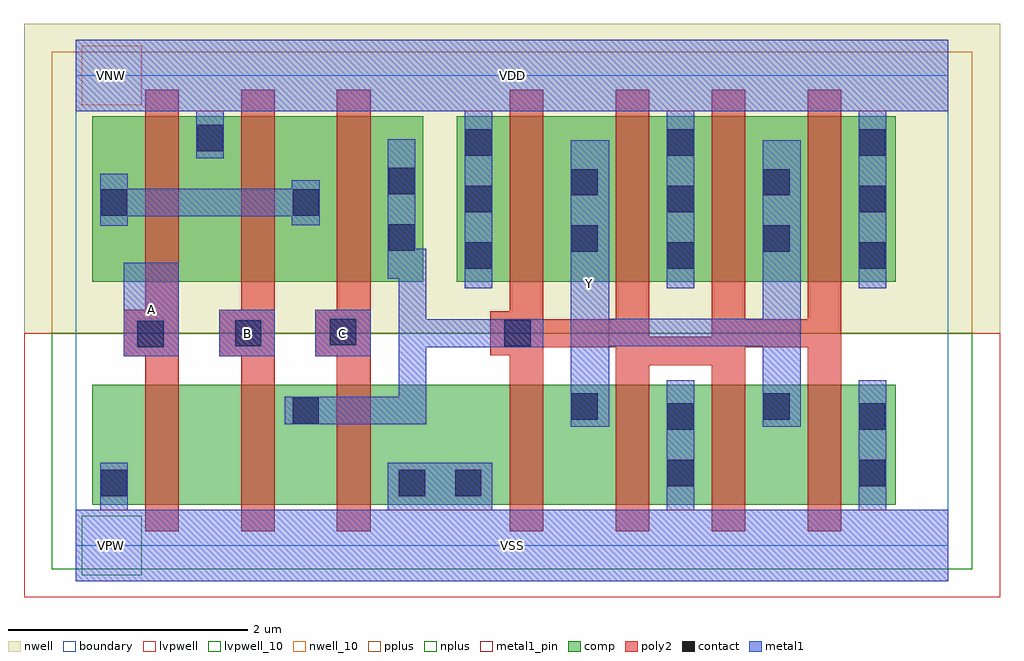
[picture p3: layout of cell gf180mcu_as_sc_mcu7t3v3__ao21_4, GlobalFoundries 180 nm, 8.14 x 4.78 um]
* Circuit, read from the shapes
.subckt gf180mcu_as_sc_mcu7t3v3__ao21_4 A B C VDD VNW VSS Y
XM1 n1 A VSS VSUBS nfet_03v3 w=1u l=0.28u
XM2 n2 B n1 VSUBS nfet_03v3 w=1u l=0.28u
XM3 VSS C n2 VSUBS nfet_03v3 w=1u l=0.28u
XM4 Y n2 VSS VSUBS nfet_03v3 w=1u l=0.28u m=4
XM5 VDD A n3 VNW pfet_03v3 w=1.38u l=0.28u
XM6 n3 B VDD VNW pfet_03v3 w=1.38u l=0.28u
XM7 n2 C n3 VNW pfet_03v3 w=1.38u l=0.28u
XM8 Y n2 VDD VNW pfet_03v3 w=1.38u l=0.28u m=4
.ends

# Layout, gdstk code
import gdstk
lib = gdstk.Library(unit=1e-6, precision=1e-09)
def R(c, l, rs):  # rectangles x0, y0, x1, y1
    for r in rs: c.add(gdstk.rectangle(r[:2], r[2:], *l))
def A(c, l, x, y, w, h, nx, ny, dx, dy):  # array of equal rectangles
    R(c, l, [(x+i*dx, y+j*dy, x+i*dx+w, y+j*dy+h) for i in range(nx) for j in range(ny)])
boundary = (0, 0)
nwell = (21, 0)
nwell_10 = (21, 10)
comp = (22, 0)
poly2 = (30, 0)
pplus = (31, 0)
nplus = (32, 0)
contact = (33, 0)
metal1 = (34, 0)
metal1_pin = (34, 10)
lvpwell = (204, 0)
lvpwell_10 = (204, 10)

gf180mcu_as_sc_mcu7t3v3_ = lib.new_cell('gf180mcu_as_sc_mcu7t3v3__ao21_4')
R(gf180mcu_as_sc_mcu7t3v3_, boundary, [(0,0,7.28,3.92)])
R(gf180mcu_as_sc_mcu7t3v3_, nwell, [(-0.43,1.77,7.71,4.35)])
R(gf180mcu_as_sc_mcu7t3v3_, nwell_10, [(0.05,3.67,0.55,4.17)])
R(gf180mcu_as_sc_mcu7t3v3_, comp, [(0.14,0.34,6.84,1.34), (0.14,2.2,2.9,3.58), (3.18,2.2,6.84,3.58)])
A(gf180mcu_as_sc_mcu7t3v3_, poly2, 0.58, 0.12, 0.28, 1.46, 3, 1, 0.8, 0)
A(gf180mcu_as_sc_mcu7t3v3_, poly2, 0.4, 1.58, 0.46, 0.385, 3, 1, 0.8, 0)
A(gf180mcu_as_sc_mcu7t3v3_, poly2, 4.505, 1.885, 0.28, 1.915, 3, 1, 0.8, 0)
A(gf180mcu_as_sc_mcu7t3v3_, poly2, 0.58, 1.965, 0.28, 1.835, 3, 1, 0.8, 0)
R(gf180mcu_as_sc_mcu7t3v3_, poly2, [(3.62,0.12,3.9,1.585), (4.505,0.12,4.785,1.505), (5.305,0.12,5.585,1.505), (6.105,0.12,6.385,1.655), (4.505,1.505,5.585,1.655), (3.46,1.585,3.9,1.655), (3.46,1.655,6.385,1.74), (3.46,1.74,4.785,1.885), (5.305,1.74,6.385,1.885), (3.46,1.885,3.9,1.955), (3.62,1.955,3.9,3.8)])
R(gf180mcu_as_sc_mcu7t3v3_, pplus, [(-0.2,1.77,7.48,4.12)])
R(gf180mcu_as_sc_mcu7t3v3_, nplus, [(-0.2,-0.2,7.48,1.77)])
A(gf180mcu_as_sc_mcu7t3v3_, contact, 3.25, 2.31, 0.22, 0.22, 1, 3, 0, 0.47)
A(gf180mcu_as_sc_mcu7t3v3_, contact, 4.935, 2.31, 0.22, 0.22, 1, 3, 0, 0.47)
A(gf180mcu_as_sc_mcu7t3v3_, contact, 6.535, 2.31, 0.22, 0.22, 1, 3, 0, 0.47)
R(gf180mcu_as_sc_mcu7t3v3_, contact, [(0.21,0.41,0.43,0.63), (2.695,0.41,2.915,0.63), (3.165,0.41,3.385,0.63), (4.935,0.495,5.155,0.715), (6.535,0.495,6.755,0.715), (4.935,0.965,5.155,1.185), (6.535,0.965,6.755,1.185), (1.81,1.015,2.03,1.235), (4.135,1.05,4.355,1.27), (5.735,1.05,5.955,1.27), (0.515,1.655,0.735,1.875), (1.33,1.66,1.55,1.88), (3.575,1.66,3.795,1.88), (2.12,1.67,2.34,1.89), (4.135,2.45,4.355,2.67), (5.735,2.45,5.955,2.67), (2.61,2.46,2.83,2.68), (0.21,2.75,0.43,2.97), (1.81,2.75,2.03,2.97), (4.135,2.92,4.355,3.14), (5.735,2.92,5.955,3.14), (2.61,2.93,2.83,3.15), (1.01,3.29,1.23,3.51)])
R(gf180mcu_as_sc_mcu7t3v3_, metal1, [(0,-0.3,7.28,0.3), (0.205,0.3,0.435,0.69), (2.605,0.3,3.475,0.69), (4.93,0.3,5.16,1.38), (6.53,0.3,6.76,1.38), (4.13,0.99,4.45,1.66), (5.73,0.99,6.05,1.66), (1.745,1.01,2.925,1.24), (2.695,1.24,2.925,1.655), (0.4,1.58,0.86,2.36), (1.2,1.58,1.66,1.965), (2,1.58,2.46,1.965), (2.695,1.655,3.9,1.885), (4.13,1.66,6.05,1.89), (2.695,1.885,2.925,2.225), (4.13,1.89,4.45,3.38), (5.73,1.89,6.05,3.38), (3.245,2.145,3.475,3.62), (4.93,2.145,5.16,3.62), (6.53,2.145,6.76,3.62), (2.605,2.225,2.925,2.475), (2.605,2.475,2.835,3.39), (0.205,2.665,0.435,2.745), (1.805,2.67,2.035,2.745), (0.205,2.745,2.035,2.975), (0.205,2.975,0.435,3.1), (1.805,2.975,2.035,3.045), (1.005,3.23,1.235,3.62), (0,3.62,7.28,4.22)])
R(gf180mcu_as_sc_mcu7t3v3_, metal1_pin, [(0,-0.3,7.28,0.3), (4.13,0.99,4.45,3.38), (0.4,1.58,0.86,2.36), (1.2,1.58,1.66,1.965), (2,1.58,2.46,1.965), (0,3.62,7.28,4.22)])
R(gf180mcu_as_sc_mcu7t3v3_, lvpwell, [(-0.43,-0.43,7.71,1.77)])
R(gf180mcu_as_sc_mcu7t3v3_, lvpwell_10, [(0.05,-0.25,0.55,0.25)])
gf180mcu_as_sc_mcu7t3v3_.add(gdstk.Label('VDD', (3.64,3.92), layer=34, texttype=10))
gf180mcu_as_sc_mcu7t3v3_.add(gdstk.Label('VSS', (3.64,0), layer=34, texttype=10))
gf180mcu_as_sc_mcu7t3v3_.add(gdstk.Label('Y', (4.29,2.185), layer=34, texttype=10))
gf180mcu_as_sc_mcu7t3v3_.add(gdstk.Label('A', (0.63,1.97), layer=34, texttype=10))
gf180mcu_as_sc_mcu7t3v3_.add(gdstk.Label('B', (1.43,1.772), layer=34, texttype=10))
gf180mcu_as_sc_mcu7t3v3_.add(gdstk.Label('C', (2.23,1.772), layer=34, texttype=10))
gf180mcu_as_sc_mcu7t3v3_.add(gdstk.Label('VNW', (0.3,3.92), layer=21, texttype=10))
gf180mcu_as_sc_mcu7t3v3_.add(gdstk.Label('VPW', (0.3,0), layer=204, texttype=10))

lib.write_gds('gf180mcu_as_sc_mcu7t3v3__ao21_4.gds')
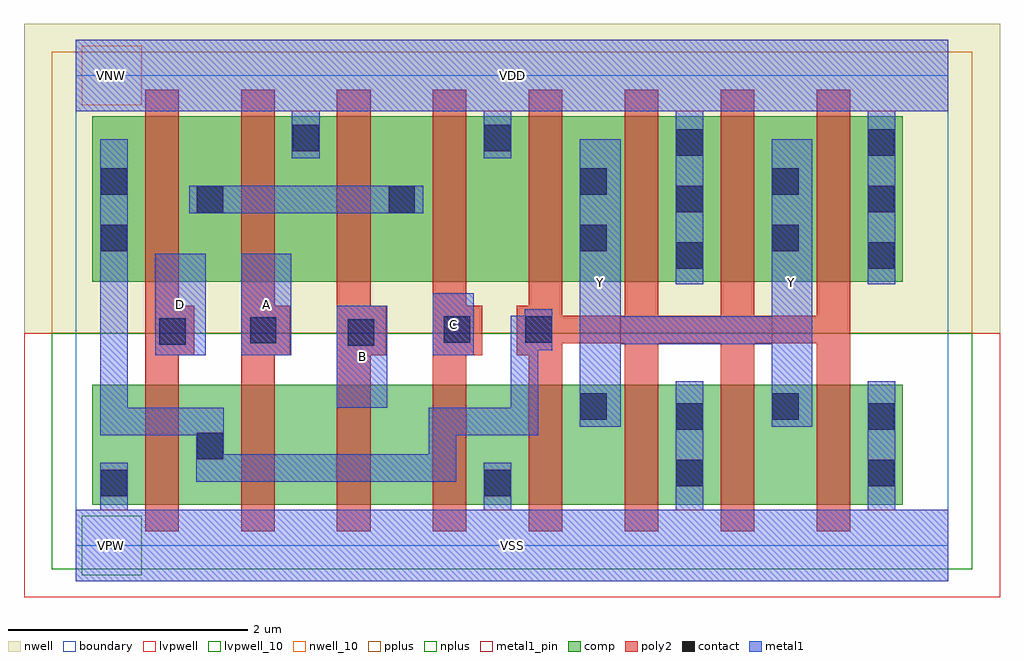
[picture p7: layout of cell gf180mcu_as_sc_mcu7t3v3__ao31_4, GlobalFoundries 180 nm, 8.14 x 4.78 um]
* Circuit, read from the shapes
.subckt gf180mcu_as_sc_mcu7t3v3__ao31_4 A B C D VDD VNW VSS Y
XM1 n1 D VSS VSUBS nfet_03v3 w=1u l=0.28u
XM2 n2 A n1 VSUBS nfet_03v3 w=1u l=0.28u
XM3 n3 B n2 VSUBS nfet_03v3 w=1u l=0.28u
XM4 VSS C n3 VSUBS nfet_03v3 w=1u l=0.28u
XM5 Y n1 VSS VSUBS nfet_03v3 w=1u l=0.28u m=4
XM6 n4 D n1 VNW pfet_03v3 w=1.38u l=0.28u
XM7 VDD A n4 VNW pfet_03v3 w=1.38u l=0.28u
XM8 n4 B VDD VNW pfet_03v3 w=1.38u l=0.28u
XM9 VDD C n4 VNW pfet_03v3 w=1.38u l=0.28u
XM10 Y n1 VDD VNW pfet_03v3 w=1.38u l=0.28u m=4
.ends

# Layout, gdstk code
import gdstk
lib = gdstk.Library(unit=1e-6, precision=1e-09)
def R(c, l, rs):  # rectangles x0, y0, x1, y1
    for r in rs: c.add(gdstk.rectangle(r[:2], r[2:], *l))
def A(c, l, x, y, w, h, nx, ny, dx, dy):  # array of equal rectangles
    R(c, l, [(x+i*dx, y+j*dy, x+i*dx+w, y+j*dy+h) for i in range(nx) for j in range(ny)])
boundary = (0, 0)
nwell = (21, 0)
nwell_10 = (21, 10)
comp = (22, 0)
poly2 = (30, 0)
pplus = (31, 0)
nplus = (32, 0)
contact = (33, 0)
metal1 = (34, 0)
metal1_pin = (34, 10)
lvpwell = (204, 0)
lvpwell_10 = (204, 10)

gf180mcu_as_sc_mcu7t3v3_ = lib.new_cell('gf180mcu_as_sc_mcu7t3v3__ao31_4')
R(gf180mcu_as_sc_mcu7t3v3_, boundary, [(0,0,7.28,3.92)])
R(gf180mcu_as_sc_mcu7t3v3_, nwell, [(-0.43,1.77,7.71,4.35)])
R(gf180mcu_as_sc_mcu7t3v3_, nwell_10, [(0.05,3.67,0.55,4.17)])
R(gf180mcu_as_sc_mcu7t3v3_, comp, [(0.14,0.34,6.9,1.34), (0.14,2.2,6.9,3.58)])
A(gf180mcu_as_sc_mcu7t3v3_, poly2, 0.58, 0.12, 0.28, 1.465, 5, 1, 0.8, 0)
A(gf180mcu_as_sc_mcu7t3v3_, poly2, 4.58, 0.12, 0.28, 1.565, 3, 1, 0.8, 0)
A(gf180mcu_as_sc_mcu7t3v3_, poly2, 0.58, 1.585, 0.41, 0.415, 4, 1, 0.8, 0)
A(gf180mcu_as_sc_mcu7t3v3_, poly2, 4.58, 1.915, 0.28, 1.885, 3, 1, 0.8, 0)
A(gf180mcu_as_sc_mcu7t3v3_, poly2, 0.58, 2, 0.28, 1.8, 5, 1, 0.8, 0)
R(gf180mcu_as_sc_mcu7t3v3_, poly2, [(3.68,1.585,4.06,1.685), (3.68,1.685,6.46,1.915), (3.68,1.915,4.06,2)])
R(gf180mcu_as_sc_mcu7t3v3_, pplus, [(-0.2,1.77,7.48,4.12)])
R(gf180mcu_as_sc_mcu7t3v3_, nplus, [(-0.2,-0.2,7.48,1.77)])
A(gf180mcu_as_sc_mcu7t3v3_, contact, 5.01, 2.31, 0.22, 0.22, 1, 3, 0, 0.47)
A(gf180mcu_as_sc_mcu7t3v3_, contact, 6.61, 2.31, 0.22, 0.22, 1, 3, 0, 0.47)
R(gf180mcu_as_sc_mcu7t3v3_, contact, [(0.21,0.41,0.43,0.63), (3.41,0.41,3.63,0.63), (5.01,0.495,5.23,0.715), (6.61,0.495,6.83,0.715), (1.01,0.72,1.23,0.94), (5.01,0.965,5.23,1.185), (6.61,0.965,6.83,1.185), (4.21,1.05,4.43,1.27), (5.81,1.05,6.03,1.27), (2.27,1.665,2.49,1.885), (0.7,1.675,0.92,1.895), (1.455,1.685,1.675,1.905), (3.07,1.69,3.29,1.91), (3.75,1.69,3.97,1.91), (0.21,2.455,0.43,2.675), (4.21,2.455,4.43,2.675), (5.81,2.455,6.03,2.675), (1.01,2.775,1.23,2.995), (2.61,2.775,2.83,2.995), (0.21,2.925,0.43,3.145), (4.21,2.925,4.43,3.145), (5.81,2.925,6.03,3.145), (1.81,3.29,2.03,3.51), (3.41,3.29,3.63,3.51)])
R(gf180mcu_as_sc_mcu7t3v3_, metal1, [(0,-0.3,7.28,0.3), (0.205,0.3,0.435,0.69), (3.405,0.3,3.635,0.69), (5.005,0.3,5.235,1.37), (6.605,0.3,6.835,1.37), (1.005,0.53,3.175,0.76), (1.005,0.76,1.235,0.92), (2.945,0.76,3.175,0.92), (0.205,0.92,1.235,1.15), (2.945,0.92,3.86,1.15), (4.205,0.99,4.545,1.68), (5.805,0.99,6.145,1.68), (0.205,1.15,0.435,3.39), (2.18,1.15,2.6,2), (3.63,1.15,3.86,1.63), (0.665,1.585,1.085,2.435), (1.38,1.585,1.8,2.435), (2.98,1.585,3.32,2.105), (3.63,1.63,3.975,1.915), (4.205,1.68,6.145,1.91), (4.205,1.91,4.545,3.39), (5.805,1.91,6.145,3.39), (3.745,1.915,3.975,1.97), (5.005,2.18,5.235,3.62), (6.605,2.18,6.835,3.62), (0.95,2.77,2.9,3), (1.805,3.23,2.035,3.62), (3.405,3.23,3.635,3.62), (0,3.62,7.28,4.22)])
R(gf180mcu_as_sc_mcu7t3v3_, metal1_pin, [(0,-0.3,7.28,0.3), (4.205,0.99,4.545,3.39), (5.805,0.99,6.145,3.39), (2.18,1.15,2.6,2), (0.665,1.585,1.085,2.435), (1.38,1.585,1.8,2.435), (2.98,1.585,3.32,2.105), (0,3.62,7.28,4.22)])
R(gf180mcu_as_sc_mcu7t3v3_, lvpwell, [(-0.43,-0.43,7.71,1.77)])
R(gf180mcu_as_sc_mcu7t3v3_, lvpwell_10, [(0.05,-0.25,0.55,0.25)])
gf180mcu_as_sc_mcu7t3v3_.add(gdstk.Label('VDD', (3.64,3.92), layer=34, texttype=10))
gf180mcu_as_sc_mcu7t3v3_.add(gdstk.Label('VSS', (3.64,0), layer=34, texttype=10))
gf180mcu_as_sc_mcu7t3v3_.add(gdstk.Label('D', (0.875,2.01), layer=34, texttype=10))
gf180mcu_as_sc_mcu7t3v3_.add(gdstk.Label('A', (1.59,2.01), layer=34, texttype=10))
gf180mcu_as_sc_mcu7t3v3_.add(gdstk.Label('B', (2.39,1.575), layer=34, texttype=10))
gf180mcu_as_sc_mcu7t3v3_.add(gdstk.Label('C', (3.15,1.845), layer=34, texttype=10))
gf180mcu_as_sc_mcu7t3v3_.add(gdstk.Label('Y', (5.975,2.19), layer=34, texttype=10))
gf180mcu_as_sc_mcu7t3v3_.add(gdstk.Label('Y', (4.375,2.19), layer=34, texttype=10))
gf180mcu_as_sc_mcu7t3v3_.add(gdstk.Label('VNW', (0.3,3.92), layer=21, texttype=10))
gf180mcu_as_sc_mcu7t3v3_.add(gdstk.Label('VPW', (0.3,0), layer=204, texttype=10))

lib.write_gds('gf180mcu_as_sc_mcu7t3v3__ao31_4.gds')
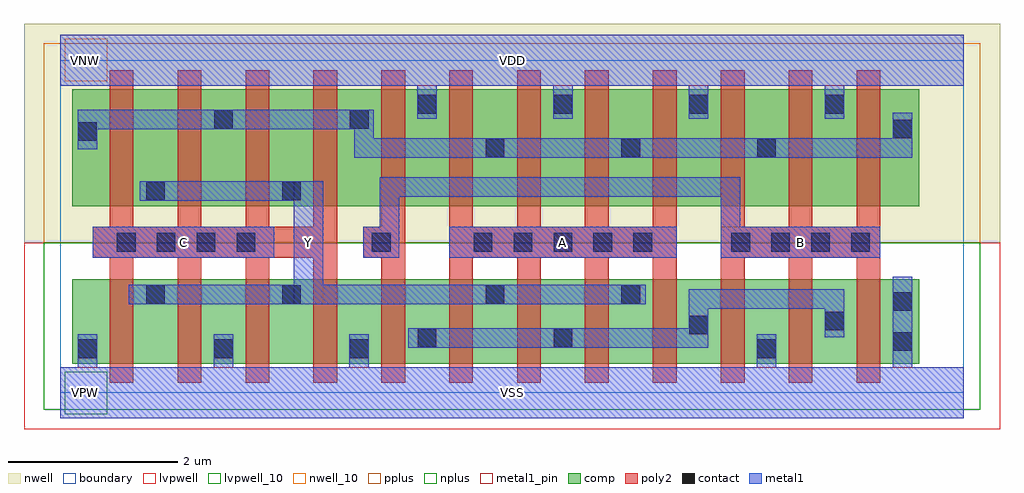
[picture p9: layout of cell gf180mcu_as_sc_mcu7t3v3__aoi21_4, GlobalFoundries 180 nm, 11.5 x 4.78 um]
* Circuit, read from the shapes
.subckt gf180mcu_as_sc_mcu7t3v3__aoi21_4 A B C VDD VNW VSS Y
XM1 Y C VSS VSUBS nfet_03v3 w=1u l=0.28u m=4
XM2 n1 B VSS VSUBS nfet_03v3 w=1u l=0.28u m=4
XM3 Y A n1 VSUBS nfet_03v3 w=1u l=0.28u m=4
XM4 Y C n2 VNW pfet_03v3 w=1.38u l=0.28u m=4
XM5 VDD B n2 VNW pfet_03v3 w=1.38u l=0.28u m=4
XM6 n2 A VDD VNW pfet_03v3 w=1.38u l=0.28u m=4
.ends

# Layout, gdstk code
import gdstk
lib = gdstk.Library(unit=1e-6, precision=1e-09)
def R(c, l, rs):  # rectangles x0, y0, x1, y1
    for r in rs: c.add(gdstk.rectangle(r[:2], r[2:], *l))
def A(c, l, x, y, w, h, nx, ny, dx, dy):  # array of equal rectangles
    R(c, l, [(x+i*dx, y+j*dy, x+i*dx+w, y+j*dy+h) for i in range(nx) for j in range(ny)])
boundary = (0, 0)
nwell = (21, 0)
nwell_10 = (21, 10)
comp = (22, 0)
poly2 = (30, 0)
pplus = (31, 0)
nplus = (32, 0)
contact = (33, 0)
metal1 = (34, 0)
metal1_pin = (34, 10)
lvpwell = (204, 0)
lvpwell_10 = (204, 10)

gf180mcu_as_sc_mcu7t3v3_ = lib.new_cell('gf180mcu_as_sc_mcu7t3v3__aoi21_4')
R(gf180mcu_as_sc_mcu7t3v3_, boundary, [(0,0,10.64,3.92)])
R(gf180mcu_as_sc_mcu7t3v3_, nwell, [(-0.43,1.77,11.07,4.35)])
R(gf180mcu_as_sc_mcu7t3v3_, nwell_10, [(0.05,3.67,0.55,4.17)])
R(gf180mcu_as_sc_mcu7t3v3_, comp, [(0.14,0.34,10.12,1.34), (0.14,2.2,10.12,3.58)])
A(gf180mcu_as_sc_mcu7t3v3_, poly2, 0.58, 0.12, 0.28, 1.47, 12, 1, 0.8, 0)
A(gf180mcu_as_sc_mcu7t3v3_, poly2, 0.58, 1.955, 0.28, 1.845, 12, 1, 0.8, 0)
R(gf180mcu_as_sc_mcu7t3v3_, poly2, [(0.38,1.59,3.26,1.955), (3.565,1.59,4.06,1.955), (4.58,1.59,7.26,1.955), (7.78,1.59,9.66,1.955)])
R(gf180mcu_as_sc_mcu7t3v3_, pplus, [(-0.2,1.77,10.84,4.12)])
R(gf180mcu_as_sc_mcu7t3v3_, nplus, [(-0.2,-0.2,10.84,1.77)])
A(gf180mcu_as_sc_mcu7t3v3_, contact, 0.21, 0.41, 0.22, 0.22, 3, 1, 1.6, 0)
A(gf180mcu_as_sc_mcu7t3v3_, contact, 0.665, 1.665, 0.22, 0.22, 4, 1, 0.47, 0)
A(gf180mcu_as_sc_mcu7t3v3_, contact, 4.87, 1.665, 0.22, 0.22, 5, 1, 0.47, 0)
A(gf180mcu_as_sc_mcu7t3v3_, contact, 7.905, 1.665, 0.22, 0.22, 4, 1, 0.47, 0)
A(gf180mcu_as_sc_mcu7t3v3_, contact, 5.01, 2.775, 0.22, 0.22, 3, 1, 1.6, 0)
A(gf180mcu_as_sc_mcu7t3v3_, contact, 4.21, 3.29, 0.22, 0.22, 4, 1, 1.6, 0)
R(gf180mcu_as_sc_mcu7t3v3_, contact, [(8.21,0.41,8.43,0.63), (9.81,0.495,10.03,0.715), (4.21,0.535,4.43,0.755), (5.81,0.535,6.03,0.755), (7.41,0.69,7.63,0.91), (9.01,0.735,9.23,0.955), (9.81,0.965,10.03,1.185), (1.01,1.05,1.23,1.27), (2.61,1.05,2.83,1.27), (5.01,1.05,5.23,1.27), (6.61,1.05,6.83,1.27), (3.67,1.665,3.89,1.885), (1.01,2.27,1.23,2.49), (2.61,2.27,2.83,2.49), (0.21,2.97,0.43,3.19), (9.81,3,10.03,3.22), (1.81,3.11,2.03,3.33), (3.41,3.11,3.63,3.33)])
A(gf180mcu_as_sc_mcu7t3v3_, metal1, 0.205, 0.3, 0.23, 0.39, 3, 1, 1.6, 0)
A(gf180mcu_as_sc_mcu7t3v3_, metal1, 4.205, 3.23, 0.23, 0.39, 4, 1, 1.6, 0)
R(gf180mcu_as_sc_mcu7t3v3_, metal1, [(0,-0.3,10.64,0.3), (8.205,0.3,8.435,0.69), (9.805,0.3,10.035,1.37), (4.1,0.53,7.635,0.76), (9.005,0.655,9.235,0.99), (7.405,0.76,7.635,0.99), (7.405,0.99,9.235,1.22), (0.805,1.045,6.895,1.275), (2.75,1.275,3.095,2.265), (0.38,1.59,2.52,1.955), (3.565,1.59,3.99,1.955), (4.58,1.59,7.26,1.955), (7.78,1.59,9.66,1.955), (3.76,1.955,3.99,2.31), (7.78,1.955,8.01,2.31), (0.935,2.265,3.095,2.495), (3.76,2.31,8.01,2.54), (3.46,2.77,10.035,3), (0.205,2.87,0.435,3.105), (3.46,3,3.69,3.105), (9.805,3,10.035,3.3), (0.205,3.105,3.69,3.335), (0,3.62,10.64,4.22)])
R(gf180mcu_as_sc_mcu7t3v3_, metal1_pin, [(0,-0.3,10.64,0.3), (2.75,1.045,3.095,2.495), (0.38,1.59,2.52,1.955), (4.58,1.59,7.26,1.955), (7.78,1.59,9.66,1.955), (0,3.62,10.64,4.22)])
R(gf180mcu_as_sc_mcu7t3v3_, lvpwell, [(-0.43,-0.43,11.07,1.77)])
R(gf180mcu_as_sc_mcu7t3v3_, lvpwell_10, [(0.05,-0.25,0.55,0.25)])
gf180mcu_as_sc_mcu7t3v3_.add(gdstk.Label('VDD', (5.32,3.92), layer=34, texttype=10))
gf180mcu_as_sc_mcu7t3v3_.add(gdstk.Label('VSS', (5.32,0), layer=34, texttype=10))
gf180mcu_as_sc_mcu7t3v3_.add(gdstk.Label('Y', (2.922,1.77), layer=34, texttype=10))
gf180mcu_as_sc_mcu7t3v3_.add(gdstk.Label('C', (1.45,1.772), layer=34, texttype=10))
gf180mcu_as_sc_mcu7t3v3_.add(gdstk.Label('B', (8.72,1.772), layer=34, texttype=10))
gf180mcu_as_sc_mcu7t3v3_.add(gdstk.Label('A', (5.92,1.772), layer=34, texttype=10))
gf180mcu_as_sc_mcu7t3v3_.add(gdstk.Label('VNW', (0.3,3.92), layer=21, texttype=10))
gf180mcu_as_sc_mcu7t3v3_.add(gdstk.Label('VPW', (0.3,0), layer=204, texttype=10))

lib.write_gds('gf180mcu_as_sc_mcu7t3v3__aoi21_4.gds')
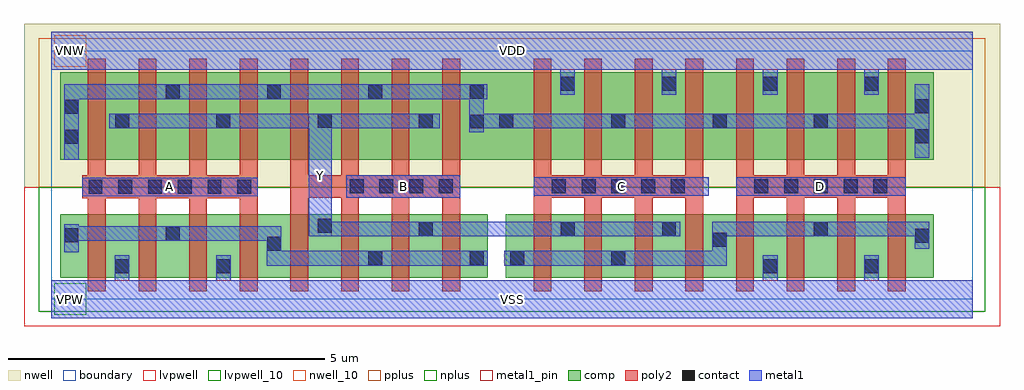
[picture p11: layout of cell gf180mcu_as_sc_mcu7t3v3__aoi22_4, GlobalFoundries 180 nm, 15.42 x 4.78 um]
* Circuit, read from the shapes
.subckt gf180mcu_as_sc_mcu7t3v3__aoi22_4 A B C D VDD VNW VSS Y
XM1 VSS A n1 VSUBS nfet_03v3 w=1u l=0.28u m=4
XM2 Y B n1 VSUBS nfet_03v3 w=1u l=0.28u m=4
XM3 Y C n2 VSUBS nfet_03v3 w=1u l=0.28u m=4
XM4 VSS D n2 VSUBS nfet_03v3 w=1u l=0.28u m=4
XM5 Y A n3 VNW pfet_03v3 w=1.38u l=0.28u m=4
XM6 Y B n3 VNW pfet_03v3 w=1.38u l=0.28u m=4
XM7 VDD C n3 VNW pfet_03v3 w=1.38u l=0.28u m=4
XM8 VDD D n3 VNW pfet_03v3 w=1.38u l=0.28u m=4
.ends

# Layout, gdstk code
import gdstk
lib = gdstk.Library(unit=1e-6, precision=1e-09)
def R(c, l, rs):  # rectangles x0, y0, x1, y1
    for r in rs: c.add(gdstk.rectangle(r[:2], r[2:], *l))
def A(c, l, x, y, w, h, nx, ny, dx, dy):  # array of equal rectangles
    R(c, l, [(x+i*dx, y+j*dy, x+i*dx+w, y+j*dy+h) for i in range(nx) for j in range(ny)])
boundary = (0, 0)
nwell = (21, 0)
nwell_10 = (21, 10)
comp = (22, 0)
poly2 = (30, 0)
pplus = (31, 0)
nplus = (32, 0)
contact = (33, 0)
metal1 = (34, 0)
metal1_pin = (34, 10)
lvpwell = (204, 0)
lvpwell_10 = (204, 10)

gf180mcu_as_sc_mcu7t3v3_ = lib.new_cell('gf180mcu_as_sc_mcu7t3v3__aoi22_4')
R(gf180mcu_as_sc_mcu7t3v3_, boundary, [(0,0,14.56,3.92)])
R(gf180mcu_as_sc_mcu7t3v3_, nwell, [(-0.43,1.77,14.99,4.35)])
R(gf180mcu_as_sc_mcu7t3v3_, nwell_10, [(0.05,3.67,0.55,4.17)])
R(gf180mcu_as_sc_mcu7t3v3_, comp, [(0.14,0.34,6.9,1.34), (7.18,0.34,13.94,1.34), (0.14,2.2,13.94,3.58)])
A(gf180mcu_as_sc_mcu7t3v3_, poly2, 0.58, 0.12, 0.28, 1.475, 4, 1, 0.8, 0)
A(gf180mcu_as_sc_mcu7t3v3_, poly2, 3.78, 0.12, 0.28, 1.48, 4, 1, 0.8, 0)
A(gf180mcu_as_sc_mcu7t3v3_, poly2, 7.62, 0.12, 0.28, 1.48, 8, 1, 0.8, 0)
A(gf180mcu_as_sc_mcu7t3v3_, poly2, 0.58, 1.955, 0.28, 1.845, 4, 1, 0.8, 0)
A(gf180mcu_as_sc_mcu7t3v3_, poly2, 3.78, 1.96, 0.28, 1.84, 4, 1, 0.8, 0)
A(gf180mcu_as_sc_mcu7t3v3_, poly2, 7.62, 1.96, 0.28, 1.84, 8, 1, 0.8, 0)
R(gf180mcu_as_sc_mcu7t3v3_, poly2, [(0.49,1.595,3.26,1.955), (3.78,1.6,6.46,1.96), (7.62,1.6,10.3,1.96), (10.82,1.6,13.5,1.96)])
R(gf180mcu_as_sc_mcu7t3v3_, pplus, [(-0.2,1.77,14.76,4.12)])
R(gf180mcu_as_sc_mcu7t3v3_, nplus, [(-0.2,-0.2,14.76,1.77)])
A(gf180mcu_as_sc_mcu7t3v3_, contact, 0.59, 1.665, 0.22, 0.22, 6, 1, 0.47, 0)
A(gf180mcu_as_sc_mcu7t3v3_, contact, 4.715, 1.67, 0.22, 0.22, 4, 1, 0.47, 0)
A(gf180mcu_as_sc_mcu7t3v3_, contact, 7.91, 1.67, 0.22, 0.22, 5, 1, 0.47, 0)
A(gf180mcu_as_sc_mcu7t3v3_, contact, 11.11, 1.67, 0.22, 0.22, 5, 1, 0.47, 0)
A(gf180mcu_as_sc_mcu7t3v3_, contact, 1.01, 2.705, 0.22, 0.22, 4, 1, 1.6, 0)
A(gf180mcu_as_sc_mcu7t3v3_, contact, 8.85, 2.705, 0.22, 0.22, 3, 1, 1.6, 0)
A(gf180mcu_as_sc_mcu7t3v3_, contact, 1.81, 3.165, 0.22, 0.22, 4, 1, 1.6, 0)
A(gf180mcu_as_sc_mcu7t3v3_, contact, 8.05, 3.29, 0.22, 0.22, 4, 1, 1.6, 0)
R(gf180mcu_as_sc_mcu7t3v3_, contact, [(1.01,0.41,1.23,0.63), (2.61,0.41,2.83,0.63), (11.25,0.41,11.47,0.63), (12.85,0.41,13.07,0.63), (5.01,0.535,5.23,0.755), (6.61,0.535,6.83,0.755), (7.25,0.535,7.47,0.755), (8.85,0.535,9.07,0.755), (3.41,0.765,3.63,0.985), (10.45,0.825,10.67,1.045), (13.65,0.89,13.87,1.11), (0.21,0.9,0.43,1.12), (1.81,0.925,2.03,1.145), (5.81,0.995,6.03,1.215), (8.05,0.995,8.27,1.215), (9.65,0.995,9.87,1.215), (12.05,0.995,12.27,1.215), (4.21,1.05,4.43,1.27), (0.21,2.455,0.43,2.675), (13.65,2.465,13.87,2.685), (6.61,2.695,6.83,2.915), (7.08,2.705,7.3,2.925), (0.21,2.925,0.43,3.145), (13.65,2.935,13.87,3.155)])
A(gf180mcu_as_sc_mcu7t3v3_, metal1, 8.045, 3.23, 0.23, 0.39, 4, 1, 1.6, 0)
R(gf180mcu_as_sc_mcu7t3v3_, metal1, [(0,-0.3,14.56,0.3), (1.005,0.3,1.235,0.69), (2.605,0.3,2.835,0.69), (11.245,0.3,11.475,0.69), (12.845,0.3,13.075,0.69), (3.405,0.53,6.895,0.76), (7.16,0.53,10.675,0.76), (0.205,0.74,0.435,0.92), (3.405,0.76,3.635,0.92), (10.445,0.76,10.675,0.99), (13.645,0.795,13.875,0.99), (0.205,0.92,3.635,1.15), (4.07,0.99,9.94,1.22), (10.445,0.99,13.875,1.22), (0.205,1.15,0.435,1.185), (4.07,1.22,4.435,2.7), (4.665,1.6,6.46,1.96), (0.49,1.625,3.26,1.92), (7.62,1.63,10.39,1.925), (10.82,1.63,13.5,1.925), (0.205,2.2,0.435,3.16), (13.645,2.235,13.875,2.7), (6.605,2.635,6.835,2.7), (0.915,2.7,6.135,2.93), (6.605,2.7,13.875,2.93), (6.605,2.93,6.835,3.16), (13.645,2.93,13.875,3.39), (0.205,3.16,6.89,3.39), (0,3.62,14.56,4.22)])
R(gf180mcu_as_sc_mcu7t3v3_, metal1_pin, [(0,-0.3,14.56,0.3), (4.07,0.99,4.435,2.93), (4.665,1.6,6.46,1.96), (0.49,1.625,3.26,1.92), (7.62,1.63,10.39,1.925), (10.82,1.63,13.5,1.925), (0,3.62,14.56,4.22)])
R(gf180mcu_as_sc_mcu7t3v3_, lvpwell, [(-0.43,-0.43,14.99,1.77)])
R(gf180mcu_as_sc_mcu7t3v3_, lvpwell_10, [(0.05,-0.25,0.55,0.25)])
gf180mcu_as_sc_mcu7t3v3_.add(gdstk.Label('VDD', (7.28,3.92), layer=34, texttype=10))
gf180mcu_as_sc_mcu7t3v3_.add(gdstk.Label('VSS', (7.28,0), layer=34, texttype=10))
gf180mcu_as_sc_mcu7t3v3_.add(gdstk.Label('Y', (4.252,1.96), layer=34, texttype=10))
gf180mcu_as_sc_mcu7t3v3_.add(gdstk.Label('A', (1.875,1.772), layer=34, texttype=10))
gf180mcu_as_sc_mcu7t3v3_.add(gdstk.Label('B', (5.562,1.78), layer=34, texttype=10))
gf180mcu_as_sc_mcu7t3v3_.add(gdstk.Label('C', (9.005,1.777), layer=34, texttype=10))
gf180mcu_as_sc_mcu7t3v3_.add(gdstk.Label('D', (12.16,1.777), layer=34, texttype=10))
gf180mcu_as_sc_mcu7t3v3_.add(gdstk.Label('VNW', (0.3,3.92), layer=21, texttype=10))
gf180mcu_as_sc_mcu7t3v3_.add(gdstk.Label('VPW', (0.3,0), layer=204, texttype=10))

lib.write_gds('gf180mcu_as_sc_mcu7t3v3__aoi22_4.gds')
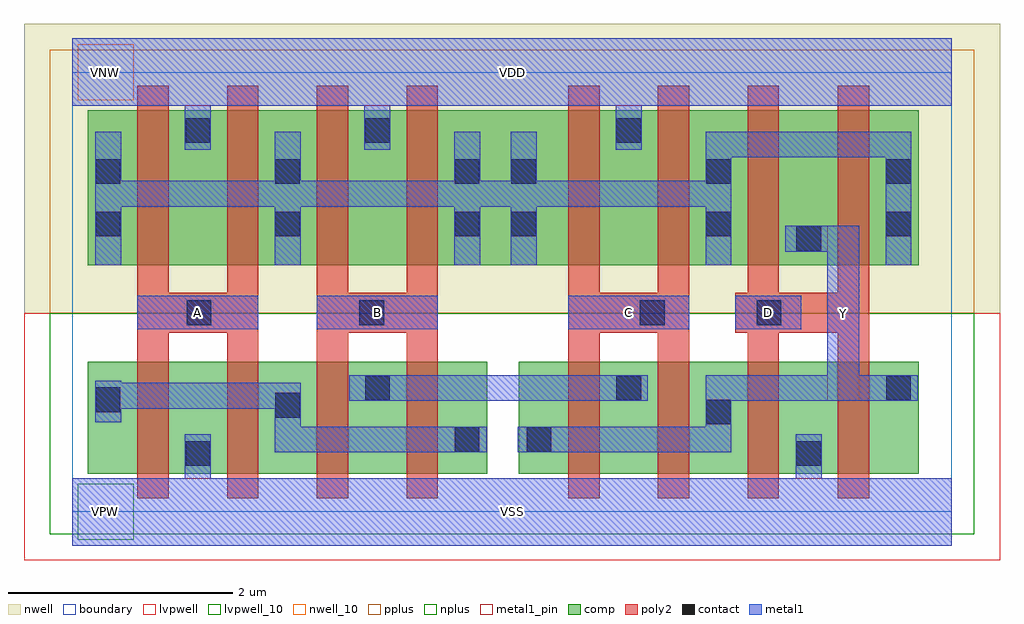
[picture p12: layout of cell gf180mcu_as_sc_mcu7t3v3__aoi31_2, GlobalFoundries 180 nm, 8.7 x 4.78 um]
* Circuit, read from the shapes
.subckt gf180mcu_as_sc_mcu7t3v3__aoi31_2 A B C D VDD VNW VSS Y
XM1 VSS A n1 VSUBS nfet_03v3 w=1u l=0.28u m=2
XM2 n2 B n1 VSUBS nfet_03v3 w=1u l=0.28u m=2
XM3 n2 C Y VSUBS nfet_03v3 w=1u l=0.28u m=2
XM4 VSS D Y VSUBS nfet_03v3 w=1u l=0.28u m=2
XM5 VDD A n3 VNW pfet_03v3 w=1.38u l=0.28u m=2
XM6 VDD B n3 VNW pfet_03v3 w=1.38u l=0.28u m=2
XM7 VDD C n3 VNW pfet_03v3 w=1.38u l=0.28u m=2
XM8 Y D n3 VNW pfet_03v3 w=1.38u l=0.28u m=2
.ends

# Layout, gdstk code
import gdstk
lib = gdstk.Library(unit=1e-6, precision=1e-09)
def R(c, l, rs):  # rectangles x0, y0, x1, y1
    for r in rs: c.add(gdstk.rectangle(r[:2], r[2:], *l))
def A(c, l, x, y, w, h, nx, ny, dx, dy):  # array of equal rectangles
    R(c, l, [(x+i*dx, y+j*dy, x+i*dx+w, y+j*dy+h) for i in range(nx) for j in range(ny)])
boundary = (0, 0)
nwell = (21, 0)
nwell_10 = (21, 10)
comp = (22, 0)
poly2 = (30, 0)
pplus = (31, 0)
nplus = (32, 0)
contact = (33, 0)
metal1 = (34, 0)
metal1_pin = (34, 10)
lvpwell = (204, 0)
lvpwell_10 = (204, 10)

gf180mcu_as_sc_mcu7t3v3_ = lib.new_cell('gf180mcu_as_sc_mcu7t3v3__aoi31_2')
R(gf180mcu_as_sc_mcu7t3v3_, boundary, [(0,0,7.84,3.92)])
R(gf180mcu_as_sc_mcu7t3v3_, nwell, [(-0.43,1.77,8.27,4.35)])
R(gf180mcu_as_sc_mcu7t3v3_, nwell_10, [(0.05,3.67,0.55,4.17)])
R(gf180mcu_as_sc_mcu7t3v3_, comp, [(0.14,0.34,3.7,1.34), (3.98,0.34,7.545,1.34), (0.14,2.2,7.545,3.58)])
A(gf180mcu_as_sc_mcu7t3v3_, poly2, 0.58, 0.12, 0.28, 1.475, 4, 1, 0.8, 0)
A(gf180mcu_as_sc_mcu7t3v3_, poly2, 4.42, 0.12, 0.28, 1.475, 3, 1, 0.8, 0)
A(gf180mcu_as_sc_mcu7t3v3_, poly2, 0.58, 1.955, 0.28, 1.845, 4, 1, 0.8, 0)
A(gf180mcu_as_sc_mcu7t3v3_, poly2, 4.42, 1.955, 0.28, 1.845, 3, 1, 0.8, 0)
R(gf180mcu_as_sc_mcu7t3v3_, poly2, [(6.825,0.12,7.105,1.595), (0.58,1.595,1.66,1.955), (2.18,1.595,3.26,1.955), (4.42,1.595,5.5,1.955), (5.91,1.595,7.105,1.955), (6.825,1.955,7.105,3.8)])
R(gf180mcu_as_sc_mcu7t3v3_, pplus, [(-0.2,1.77,8.04,4.12)])
R(gf180mcu_as_sc_mcu7t3v3_, nplus, [(-0.2,-0.2,8.04,1.77)])
A(gf180mcu_as_sc_mcu7t3v3_, contact, 0.21, 2.455, 0.22, 0.22, 3, 2, 1.6, 0.47)
R(gf180mcu_as_sc_mcu7t3v3_, contact, [(1.01,0.41,1.23,0.63), (6.455,0.41,6.675,0.63), (3.41,0.535,3.63,0.755), (4.05,0.535,4.27,0.755), (5.65,0.78,5.87,1), (1.81,0.84,2.03,1.06), (0.21,0.89,0.43,1.11), (2.61,0.995,2.83,1.215), (4.85,0.995,5.07,1.215), (7.255,0.995,7.475,1.215), (1.02,1.665,1.24,1.885), (2.56,1.665,2.78,1.885), (5.06,1.665,5.28,1.885), (6.1,1.665,6.32,1.885), (6.455,2.325,6.675,2.545), (3.915,2.455,4.135,2.675), (5.65,2.455,5.87,2.675), (7.255,2.455,7.475,2.675), (3.915,2.925,4.135,3.145), (5.65,2.925,5.87,3.145), (7.255,2.925,7.475,3.145), (1.01,3.29,1.23,3.51), (2.61,3.29,2.83,3.51), (4.85,3.29,5.07,3.51)])
A(gf180mcu_as_sc_mcu7t3v3_, metal1, 0.205, 2.2, 0.23, 0.52, 3, 1, 1.6, 0)
A(gf180mcu_as_sc_mcu7t3v3_, metal1, 0.205, 2.95, 0.23, 0.44, 3, 1, 1.6, 0)
R(gf180mcu_as_sc_mcu7t3v3_, metal1, [(0,-0.3,7.84,0.3), (1.005,0.3,1.235,0.69), (6.45,0.3,6.68,0.69), (1.805,0.53,3.695,0.76), (3.97,0.53,5.875,0.76), (1.805,0.76,2.035,0.92), (5.645,0.76,5.875,0.99), (0.205,0.8,0.435,0.92), (0.205,0.92,2.035,1.15), (2.47,0.99,5.13,1.22), (5.645,0.99,7.535,1.22), (0.205,1.15,0.435,1.17), (6.73,1.22,7.015,2.32), (0.58,1.63,1.66,1.925), (2.18,1.63,3.26,1.925), (4.42,1.63,5.5,1.925), (5.91,1.63,6.5,1.925), (3.91,2.2,4.14,2.72), (5.645,2.2,5.875,2.72), (7.25,2.2,7.48,3.16), (6.355,2.32,7.015,2.55), (0.205,2.72,5.875,2.95), (3.91,2.95,4.14,3.39), (5.645,2.95,5.875,3.16), (5.645,3.16,7.48,3.39), (1.005,3.23,1.235,3.62), (2.605,3.23,2.835,3.62), (4.845,3.23,5.075,3.62), (0,3.62,7.84,4.22)])
R(gf180mcu_as_sc_mcu7t3v3_, metal1_pin, [(0,-0.3,7.84,0.3), (6.73,0.99,7.015,2.55), (0.58,1.63,1.66,1.925), (2.18,1.63,3.26,1.925), (4.42,1.63,5.5,1.925), (5.91,1.63,6.5,1.925), (0,3.62,7.84,4.22)])
R(gf180mcu_as_sc_mcu7t3v3_, lvpwell, [(-0.43,-0.43,8.27,1.77)])
R(gf180mcu_as_sc_mcu7t3v3_, lvpwell_10, [(0.05,-0.25,0.55,0.25)])
gf180mcu_as_sc_mcu7t3v3_.add(gdstk.Label('VDD', (3.92,3.92), layer=34, texttype=10))
gf180mcu_as_sc_mcu7t3v3_.add(gdstk.Label('VSS', (3.92,0), layer=34, texttype=10))
gf180mcu_as_sc_mcu7t3v3_.add(gdstk.Label('A', (1.12,1.777), layer=34, texttype=10))
gf180mcu_as_sc_mcu7t3v3_.add(gdstk.Label('B', (2.72,1.777), layer=34, texttype=10))
gf180mcu_as_sc_mcu7t3v3_.add(gdstk.Label('C', (4.96,1.777), layer=34, texttype=10))
gf180mcu_as_sc_mcu7t3v3_.add(gdstk.Label('Y', (6.872,1.77), layer=34, texttype=10))
gf180mcu_as_sc_mcu7t3v3_.add(gdstk.Label('D', (6.205,1.777), layer=34, texttype=10))
gf180mcu_as_sc_mcu7t3v3_.add(gdstk.Label('VNW', (0.3,3.92), layer=21, texttype=10))
gf180mcu_as_sc_mcu7t3v3_.add(gdstk.Label('VPW', (0.3,0), layer=204, texttype=10))

lib.write_gds('gf180mcu_as_sc_mcu7t3v3__aoi31_2.gds')
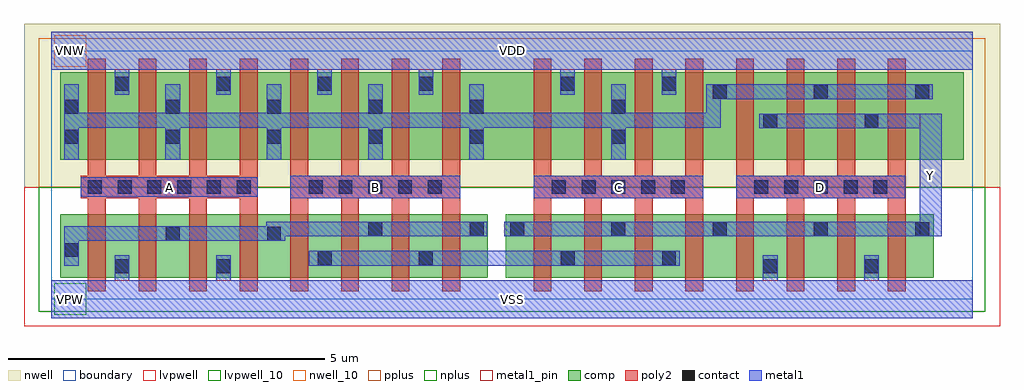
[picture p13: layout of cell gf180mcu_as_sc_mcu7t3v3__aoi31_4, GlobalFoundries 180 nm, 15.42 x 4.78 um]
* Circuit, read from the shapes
.subckt gf180mcu_as_sc_mcu7t3v3__aoi31_4 A B C D VDD VNW VSS Y
XM1 VSS A n1 VSUBS nfet_03v3 w=1u l=0.28u m=4
XM2 n2 B n1 VSUBS nfet_03v3 w=1u l=0.28u m=4
XM3 n2 C Y VSUBS nfet_03v3 w=1u l=0.28u m=4
XM4 VSS D Y VSUBS nfet_03v3 w=1u l=0.28u m=4
XM5 VDD A n3 VNW pfet_03v3 w=1.38u l=0.28u m=4
XM6 VDD B n3 VNW pfet_03v3 w=1.38u l=0.28u m=4
XM7 VDD C n3 VNW pfet_03v3 w=1.38u l=0.28u m=4
XM8 Y D n3 VNW pfet_03v3 w=1.38u l=0.28u m=4
.ends

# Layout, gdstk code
import gdstk
lib = gdstk.Library(unit=1e-6, precision=1e-09)
def R(c, l, rs):  # rectangles x0, y0, x1, y1
    for r in rs: c.add(gdstk.rectangle(r[:2], r[2:], *l))
def A(c, l, x, y, w, h, nx, ny, dx, dy):  # array of equal rectangles
    R(c, l, [(x+i*dx, y+j*dy, x+i*dx+w, y+j*dy+h) for i in range(nx) for j in range(ny)])
boundary = (0, 0)
nwell = (21, 0)
nwell_10 = (21, 10)
comp = (22, 0)
poly2 = (30, 0)
pplus = (31, 0)
nplus = (32, 0)
contact = (33, 0)
metal1 = (34, 0)
metal1_pin = (34, 10)
lvpwell = (204, 0)
lvpwell_10 = (204, 10)

gf180mcu_as_sc_mcu7t3v3_ = lib.new_cell('gf180mcu_as_sc_mcu7t3v3__aoi31_4')
R(gf180mcu_as_sc_mcu7t3v3_, boundary, [(0,0,14.56,3.92)])
R(gf180mcu_as_sc_mcu7t3v3_, nwell, [(-0.43,1.77,14.99,4.35)])
R(gf180mcu_as_sc_mcu7t3v3_, nwell_10, [(0.05,3.67,0.55,4.17)])
R(gf180mcu_as_sc_mcu7t3v3_, comp, [(0.14,0.34,6.9,1.34), (7.18,0.34,13.94,1.34), (0.14,2.2,14.42,3.58)])
A(gf180mcu_as_sc_mcu7t3v3_, poly2, 0.58, 0.12, 0.28, 1.47, 8, 1, 0.8, 0)
A(gf180mcu_as_sc_mcu7t3v3_, poly2, 7.62, 0.12, 0.28, 1.47, 8, 1, 0.8, 0)
A(gf180mcu_as_sc_mcu7t3v3_, poly2, 0.58, 1.95, 0.28, 1.85, 8, 1, 0.8, 0)
A(gf180mcu_as_sc_mcu7t3v3_, poly2, 7.62, 1.95, 0.28, 1.85, 8, 1, 0.8, 0)
R(gf180mcu_as_sc_mcu7t3v3_, poly2, [(0.47,1.59,3.265,1.95), (3.78,1.59,6.46,1.95), (7.62,1.59,10.3,1.95), (10.82,1.59,13.5,1.95)])
R(gf180mcu_as_sc_mcu7t3v3_, pplus, [(-0.2,1.77,14.76,4.12)])
R(gf180mcu_as_sc_mcu7t3v3_, nplus, [(-0.2,-0.2,14.76,1.77)])
A(gf180mcu_as_sc_mcu7t3v3_, contact, 7.25, 0.995, 0.22, 0.22, 5, 1, 1.6, 0)
A(gf180mcu_as_sc_mcu7t3v3_, contact, 0.58, 1.66, 0.22, 0.22, 6, 1, 0.47, 0)
A(gf180mcu_as_sc_mcu7t3v3_, contact, 4.07, 1.66, 0.22, 0.22, 5, 1, 0.47, 0)
A(gf180mcu_as_sc_mcu7t3v3_, contact, 7.91, 1.66, 0.22, 0.22, 5, 1, 0.47, 0)
A(gf180mcu_as_sc_mcu7t3v3_, contact, 11.11, 1.66, 0.22, 0.22, 5, 1, 0.47, 0)
A(gf180mcu_as_sc_mcu7t3v3_, contact, 0.21, 2.455, 0.22, 0.22, 5, 2, 1.6, 0.47)
A(gf180mcu_as_sc_mcu7t3v3_, contact, 10.45, 3.165, 0.22, 0.22, 3, 1, 1.6, 0)
A(gf180mcu_as_sc_mcu7t3v3_, contact, 1.01, 3.29, 0.22, 0.22, 4, 1, 1.6, 0)
R(gf180mcu_as_sc_mcu7t3v3_, contact, [(1.01,0.41,1.23,0.63), (2.61,0.41,2.83,0.63), (11.25,0.41,11.47,0.63), (12.85,0.41,13.07,0.63), (4.21,0.535,4.43,0.755), (5.81,0.535,6.03,0.755), (8.05,0.535,8.27,0.755), (9.65,0.535,9.87,0.755), (0.21,0.665,0.43,0.885), (1.81,0.925,2.03,1.145), (3.41,0.925,3.63,1.145), (5.01,0.995,5.23,1.215), (6.61,0.995,6.83,1.215), (8.85,2.455,9.07,2.675), (11.25,2.705,11.47,2.925), (12.85,2.705,13.07,2.925), (8.85,2.925,9.07,3.145), (8.05,3.29,8.27,3.51), (9.65,3.29,9.87,3.51)])
A(gf180mcu_as_sc_mcu7t3v3_, metal1, 0.205, 2.2, 0.23, 0.51, 5, 1, 1.6, 0)
A(gf180mcu_as_sc_mcu7t3v3_, metal1, 0.205, 2.94, 0.23, 0.45, 5, 1, 1.6, 0)
A(gf180mcu_as_sc_mcu7t3v3_, metal1, 1.005, 3.23, 0.23, 0.39, 4, 1, 1.6, 0)
R(gf180mcu_as_sc_mcu7t3v3_, metal1, [(0,-0.3,14.56,0.3), (1.005,0.3,1.235,0.69), (2.605,0.3,2.835,0.69), (11.245,0.3,11.475,0.69), (12.845,0.3,13.075,0.69), (0.205,0.53,0.435,0.92), (4.07,0.53,9.93,0.76), (0.205,0.92,3.7,0.99), (0.205,0.99,6.89,1.15), (7.155,0.99,14.07,1.22), (3.4,1.15,6.89,1.22), (13.725,1.22,14.07,2.7), (3.78,1.59,6.46,1.95), (7.62,1.59,10.3,1.95), (10.82,1.59,13.495,1.95), (0.47,1.615,3.265,1.925), (8.845,2.2,9.075,2.71), (11.185,2.7,14.07,2.93), (0.205,2.71,10.58,2.94), (8.845,2.94,9.075,3.39), (10.35,2.94,10.58,3.16), (10.35,3.16,13.93,3.39), (8.045,3.23,8.275,3.62), (9.645,3.23,9.875,3.62), (0,3.62,14.56,4.22)])
R(gf180mcu_as_sc_mcu7t3v3_, metal1_pin, [(0,-0.3,14.56,0.3), (13.725,0.99,14.07,2.93), (3.78,1.59,6.46,1.95), (7.62,1.59,10.3,1.95), (10.82,1.59,13.495,1.95), (0.47,1.615,3.265,1.925), (0,3.62,14.56,4.22)])
R(gf180mcu_as_sc_mcu7t3v3_, lvpwell, [(-0.43,-0.43,14.99,1.77)])
R(gf180mcu_as_sc_mcu7t3v3_, lvpwell_10, [(0.05,-0.25,0.55,0.25)])
gf180mcu_as_sc_mcu7t3v3_.add(gdstk.Label('VDD', (7.28,3.92), layer=34, texttype=10))
gf180mcu_as_sc_mcu7t3v3_.add(gdstk.Label('VSS', (7.28,0), layer=34, texttype=10))
gf180mcu_as_sc_mcu7t3v3_.add(gdstk.Label('A', (1.867,1.77), layer=34, texttype=10))
gf180mcu_as_sc_mcu7t3v3_.add(gdstk.Label('B', (5.12,1.77), layer=34, texttype=10))
gf180mcu_as_sc_mcu7t3v3_.add(gdstk.Label('C', (8.96,1.77), layer=34, texttype=10))
gf180mcu_as_sc_mcu7t3v3_.add(gdstk.Label('D', (12.157,1.77), layer=34, texttype=10))
gf180mcu_as_sc_mcu7t3v3_.add(gdstk.Label('Y', (13.897,1.96), layer=34, texttype=10))
gf180mcu_as_sc_mcu7t3v3_.add(gdstk.Label('VNW', (0.3,3.92), layer=21, texttype=10))
gf180mcu_as_sc_mcu7t3v3_.add(gdstk.Label('VPW', (0.3,0), layer=204, texttype=10))

lib.write_gds('gf180mcu_as_sc_mcu7t3v3__aoi31_4.gds')
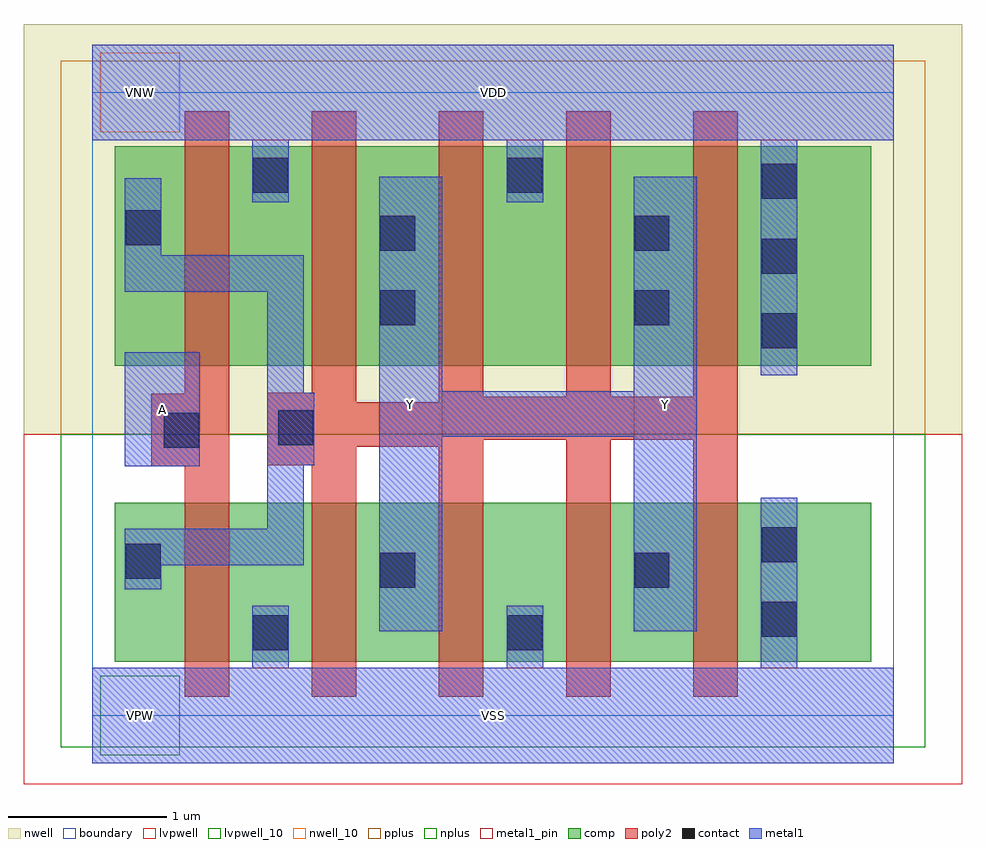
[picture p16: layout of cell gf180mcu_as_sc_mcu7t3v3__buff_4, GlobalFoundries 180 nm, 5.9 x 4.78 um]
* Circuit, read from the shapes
.subckt gf180mcu_as_sc_mcu7t3v3__buff_4 A VDD VNW VSS Y
XM1 VSS A n1 VSUBS nfet_03v3 w=1u l=0.28u
XM2 Y n1 VSS VSUBS nfet_03v3 w=1u l=0.28u m=4
XM3 VDD A n1 VNW pfet_03v3 w=1.38u l=0.28u
XM4 Y n1 VDD VNW pfet_03v3 w=1.38u l=0.28u m=4
.ends

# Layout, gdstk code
import gdstk
lib = gdstk.Library(unit=1e-6, precision=1e-09)
def R(c, l, rs):  # rectangles x0, y0, x1, y1
    for r in rs: c.add(gdstk.rectangle(r[:2], r[2:], *l))
def A(c, l, x, y, w, h, nx, ny, dx, dy):  # array of equal rectangles
    R(c, l, [(x+i*dx, y+j*dy, x+i*dx+w, y+j*dy+h) for i in range(nx) for j in range(ny)])
boundary = (0, 0)
nwell = (21, 0)
nwell_10 = (21, 10)
comp = (22, 0)
poly2 = (30, 0)
pplus = (31, 0)
nplus = (32, 0)
contact = (33, 0)
metal1 = (34, 0)
metal1_pin = (34, 10)
lvpwell = (204, 0)
lvpwell_10 = (204, 10)

gf180mcu_as_sc_mcu7t3v3_ = lib.new_cell('gf180mcu_as_sc_mcu7t3v3__buff_4')
R(gf180mcu_as_sc_mcu7t3v3_, boundary, [(0,0,5.04,3.92)])
R(gf180mcu_as_sc_mcu7t3v3_, nwell, [(-0.43,1.77,5.47,4.35)])
R(gf180mcu_as_sc_mcu7t3v3_, nwell_10, [(0.05,3.67,0.55,4.17)])
R(gf180mcu_as_sc_mcu7t3v3_, comp, [(0.14,0.34,4.9,1.34), (0.14,2.2,4.9,3.58)])
A(gf180mcu_as_sc_mcu7t3v3_, poly2, 2.18, 2.005, 0.28, 1.795, 3, 1, 0.8, 0)
R(gf180mcu_as_sc_mcu7t3v3_, poly2, [(0.58,0.12,0.86,1.57), (1.38,0.12,1.66,1.575), (2.18,0.12,2.46,1.69), (2.98,0.12,3.26,1.735), (3.78,0.12,4.06,1.735), (0.37,1.57,0.86,2.025), (1.1,1.575,1.66,1.69), (1.1,1.69,2.46,1.735), (1.1,1.735,4.06,1.97), (1.1,1.97,1.66,2.03), (2.18,1.97,4.06,2.005), (0.58,2.025,0.86,3.8), (1.38,2.03,1.66,3.8)])
R(gf180mcu_as_sc_mcu7t3v3_, pplus, [(-0.2,1.77,5.24,4.12)])
R(gf180mcu_as_sc_mcu7t3v3_, nplus, [(-0.2,-0.2,5.24,1.77)])
A(gf180mcu_as_sc_mcu7t3v3_, contact, 4.21, 2.31, 0.22, 0.22, 1, 3, 0, 0.47)
R(gf180mcu_as_sc_mcu7t3v3_, contact, [(1.01,0.41,1.23,0.63), (2.61,0.41,2.83,0.63), (4.21,0.495,4.43,0.715), (1.81,0.805,2.03,1.025), (3.41,0.805,3.63,1.025), (0.21,0.86,0.43,1.08), (4.21,0.965,4.43,1.185), (0.45,1.685,0.67,1.905), (1.17,1.7,1.39,1.92), (1.81,2.455,2.03,2.675), (3.41,2.455,3.63,2.675), (1.81,2.925,2.03,3.145), (3.41,2.925,3.63,3.145), (0.21,2.96,0.43,3.18), (1.01,3.29,1.23,3.51), (2.61,3.29,2.83,3.51)])
R(gf180mcu_as_sc_mcu7t3v3_, metal1, [(0,-0.3,5.04,0.3), (1.005,0.3,1.235,0.69), (2.605,0.3,2.835,0.69), (4.205,0.3,4.435,1.37), (1.805,0.53,2.2,1.755), (3.405,0.53,3.8,1.755), (0.205,0.795,0.435,0.945), (0.205,0.945,1.33,1.175), (1.1,1.175,1.33,1.575), (0.205,1.57,0.675,2.285), (1.1,1.575,1.395,2.03), (1.805,1.755,3.8,2.04), (1.1,2.03,1.33,2.665), (1.805,2.04,2.2,3.39), (3.405,2.04,3.8,3.39), (4.205,2.14,4.435,3.62), (0.205,2.665,1.33,2.895), (0.205,2.895,0.435,3.38), (1.005,3.23,1.235,3.62), (2.605,3.23,2.835,3.62), (0,3.62,5.04,4.22)])
R(gf180mcu_as_sc_mcu7t3v3_, metal1_pin, [(0,-0.3,5.04,0.3), (1.805,0.53,2.2,3.39), (3.405,0.53,3.8,3.39), (0.205,1.57,0.675,2.285), (0,3.62,5.04,4.22)])
R(gf180mcu_as_sc_mcu7t3v3_, lvpwell, [(-0.43,-0.43,5.47,1.77)])
R(gf180mcu_as_sc_mcu7t3v3_, lvpwell_10, [(0.05,-0.25,0.55,0.25)])
gf180mcu_as_sc_mcu7t3v3_.add(gdstk.Label('VDD', (2.52,3.92), layer=34, texttype=10))
gf180mcu_as_sc_mcu7t3v3_.add(gdstk.Label('VSS', (2.52,0), layer=34, texttype=10))
gf180mcu_as_sc_mcu7t3v3_.add(gdstk.Label('A', (0.44,1.927), layer=34, texttype=10))
gf180mcu_as_sc_mcu7t3v3_.add(gdstk.Label('Y', (3.602,1.96), layer=34, texttype=10))
gf180mcu_as_sc_mcu7t3v3_.add(gdstk.Label('Y', (2.002,1.96), layer=34, texttype=10))
gf180mcu_as_sc_mcu7t3v3_.add(gdstk.Label('VNW', (0.3,3.92), layer=21, texttype=10))
gf180mcu_as_sc_mcu7t3v3_.add(gdstk.Label('VPW', (0.3,0), layer=204, texttype=10))

lib.write_gds('gf180mcu_as_sc_mcu7t3v3__buff_4.gds')
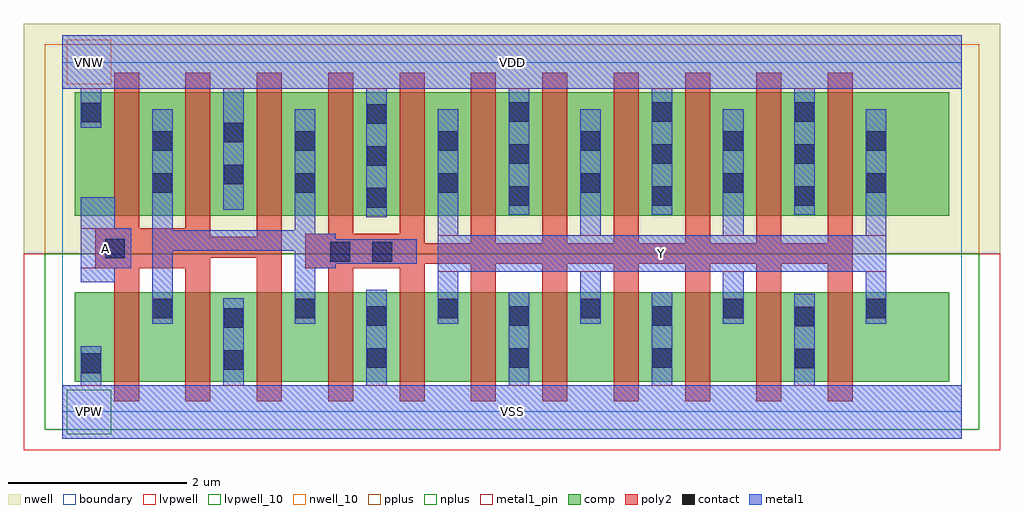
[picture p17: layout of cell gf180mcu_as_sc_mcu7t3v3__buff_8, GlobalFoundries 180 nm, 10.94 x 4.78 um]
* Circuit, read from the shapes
.subckt gf180mcu_as_sc_mcu7t3v3__buff_8 A VDD VNW VSS Y
XM1 n1 A VSS VSUBS nfet_03v3 w=1u l=0.28u m=3
XM2 VSS n1 n1 VSUBS nfet_03v3 w=1u l=0.28u
XM3 Y n1 VSS VSUBS nfet_03v3 w=1u l=0.28u m=7
XM4 n1 A VDD VNW pfet_03v3 w=1.38u l=0.28u m=3
XM5 VDD n1 n1 VNW pfet_03v3 w=1.38u l=0.28u
XM6 Y n1 VDD VNW pfet_03v3 w=1.38u l=0.28u m=7
.ends

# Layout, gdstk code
import gdstk
lib = gdstk.Library(unit=1e-6, precision=1e-09)
def R(c, l, rs):  # rectangles x0, y0, x1, y1
    for r in rs: c.add(gdstk.rectangle(r[:2], r[2:], *l))
def A(c, l, x, y, w, h, nx, ny, dx, dy):  # array of equal rectangles
    R(c, l, [(x+i*dx, y+j*dy, x+i*dx+w, y+j*dy+h) for i in range(nx) for j in range(ny)])
boundary = (0, 0)
nwell = (21, 0)
nwell_10 = (21, 10)
comp = (22, 0)
poly2 = (30, 0)
pplus = (31, 0)
nplus = (32, 0)
contact = (33, 0)
metal1 = (34, 0)
metal1_pin = (34, 10)
lvpwell = (204, 0)
lvpwell_10 = (204, 10)

gf180mcu_as_sc_mcu7t3v3_ = lib.new_cell('gf180mcu_as_sc_mcu7t3v3__buff_8')
R(gf180mcu_as_sc_mcu7t3v3_, boundary, [(0,0,10.08,3.92)])
R(gf180mcu_as_sc_mcu7t3v3_, nwell, [(-0.43,1.77,10.51,4.35)])
R(gf180mcu_as_sc_mcu7t3v3_, nwell_10, [(0.05,3.67,0.55,4.17)])
R(gf180mcu_as_sc_mcu7t3v3_, comp, [(0.14,0.34,9.94,1.34), (0.14,2.2,9.94,3.58)])
A(gf180mcu_as_sc_mcu7t3v3_, poly2, 4.58, 0.12, 0.28, 1.54, 6, 1, 0.8, 0)
A(gf180mcu_as_sc_mcu7t3v3_, poly2, 4.58, 1.89, 0.28, 1.91, 6, 1, 0.8, 0)
R(gf180mcu_as_sc_mcu7t3v3_, poly2, [(0.58,0.12,0.86,1.61), (1.38,0.12,1.66,1.61), (2.18,0.12,2.46,1.725), (2.98,0.12,3.26,1.61), (3.78,0.12,4.06,1.61), (0.37,1.61,1.66,1.725), (2.72,1.61,4.06,1.66), (2.72,1.66,8.86,1.89), (0.37,1.725,2.46,1.965), (2.72,1.89,4.06,1.995), (0.37,1.965,1.66,2.06), (2.18,1.965,2.46,3.8), (2.98,1.995,3.26,3.8), (3.78,1.995,4.06,3.8), (0.58,2.06,0.86,3.8), (1.38,2.06,1.66,3.8)])
R(gf180mcu_as_sc_mcu7t3v3_, pplus, [(-0.2,1.77,10.28,4.12)])
R(gf180mcu_as_sc_mcu7t3v3_, nplus, [(-0.2,-0.2,10.28,1.77)])
A(gf180mcu_as_sc_mcu7t3v3_, contact, 3.41, 0.495, 0.22, 0.22, 3, 2, 1.6, 0.47)
A(gf180mcu_as_sc_mcu7t3v3_, contact, 1.01, 1.05, 0.22, 0.22, 6, 2, 1.6, 1.405)
A(gf180mcu_as_sc_mcu7t3v3_, contact, 3.41, 2.29, 0.22, 0.22, 1, 3, 0, 0.47)
A(gf180mcu_as_sc_mcu7t3v3_, contact, 5.01, 2.31, 0.22, 0.22, 3, 3, 1.6, 0.47)
A(gf180mcu_as_sc_mcu7t3v3_, contact, 1.01, 2.925, 0.22, 0.22, 6, 1, 1.6, 0)
R(gf180mcu_as_sc_mcu7t3v3_, contact, [(0.21,0.435,0.43,0.655), (1.81,0.47,2.03,0.69), (8.21,0.49,8.43,0.71), (1.81,0.94,2.03,1.16), (8.21,0.96,8.43,1.18), (3.005,1.685,3.225,1.905), (3.475,1.685,3.695,1.905), (0.48,1.72,0.7,1.94), (1.81,2.55,2.03,2.77), (1.81,3.02,2.03,3.24), (0.21,3.245,0.43,3.465)])
A(gf180mcu_as_sc_mcu7t3v3_, metal1, 4.205, 0.99, 0.23, 0.58, 4, 1, 1.6, 0)
A(gf180mcu_as_sc_mcu7t3v3_, metal1, 4.205, 1.98, 0.23, 1.41, 4, 1, 1.6, 0)
A(gf180mcu_as_sc_mcu7t3v3_, metal1, 5.005, 2.21, 0.23, 1.41, 3, 1, 1.6, 0)
R(gf180mcu_as_sc_mcu7t3v3_, metal1, [(0,-0.3,10.08,0.3), (0.205,0.3,0.435,0.735), (1.805,0.3,2.035,1.275), (3.405,0.3,3.635,1.37), (5.005,0.3,5.235,1.34), (6.605,0.3,6.835,1.34), (8.205,0.3,8.435,1.325), (1.005,0.99,1.235,1.805), (2.605,0.99,2.835,1.61), (0.205,1.455,0.585,1.61), (4.205,1.57,9.235,1.98), (0.205,1.61,0.77,2.06), (2.605,1.61,3.065,1.66), (2.605,1.66,3.975,1.805), (1.005,1.805,3.975,1.935), (1.005,1.935,3.065,1.995), (1.005,1.995,2.835,2.035), (1.005,2.035,1.235,3.39), (2.605,2.035,2.835,3.39), (0.205,2.06,0.585,2.405), (3.405,2.18,3.635,3.62), (1.805,2.265,2.035,3.62), (0.205,3.185,0.435,3.62), (0,3.62,10.08,4.22)])
R(gf180mcu_as_sc_mcu7t3v3_, metal1_pin, [(0,-0.3,10.08,0.3), (4.205,1.57,9.235,1.98), (0.205,1.61,0.77,2.06), (0,3.62,10.08,4.22)])
R(gf180mcu_as_sc_mcu7t3v3_, lvpwell, [(-0.43,-0.43,10.51,1.77)])
R(gf180mcu_as_sc_mcu7t3v3_, lvpwell_10, [(0.05,-0.25,0.55,0.25)])
gf180mcu_as_sc_mcu7t3v3_.add(gdstk.Label('VDD', (5.04,3.92), layer=34, texttype=10))
gf180mcu_as_sc_mcu7t3v3_.add(gdstk.Label('VSS', (5.04,0), layer=34, texttype=10))
gf180mcu_as_sc_mcu7t3v3_.add(gdstk.Label('A', (0.487,1.835), layer=34, texttype=10))
gf180mcu_as_sc_mcu7t3v3_.add(gdstk.Label('Y', (6.72,1.775), layer=34, texttype=10))
gf180mcu_as_sc_mcu7t3v3_.add(gdstk.Label('VNW', (0.3,3.92), layer=21, texttype=10))
gf180mcu_as_sc_mcu7t3v3_.add(gdstk.Label('VPW', (0.3,0), layer=204, texttype=10))

lib.write_gds('gf180mcu_as_sc_mcu7t3v3__buff_8.gds')
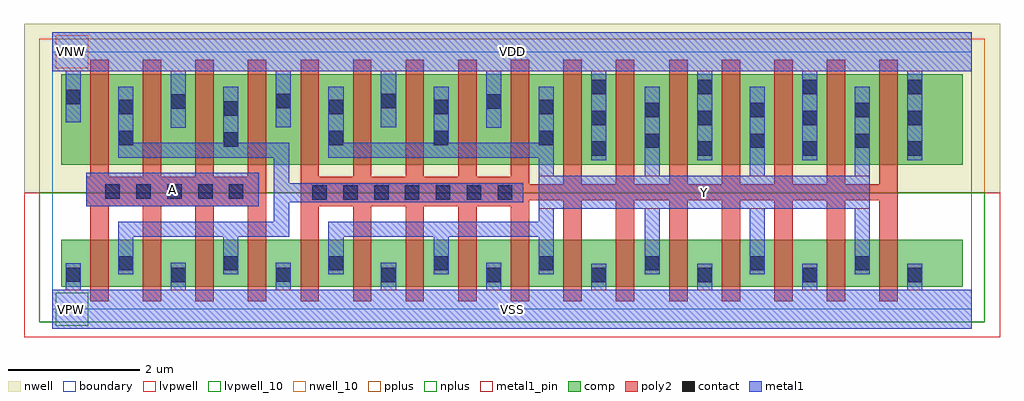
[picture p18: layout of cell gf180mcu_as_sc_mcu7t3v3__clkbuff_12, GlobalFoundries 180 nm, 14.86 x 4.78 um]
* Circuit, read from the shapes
.subckt gf180mcu_as_sc_mcu7t3v3__clkbuff_12 A VDD VNW VSS Y
XM1 n1 A VSS VSUBS nfet_03v3 w=0.72u l=0.28u m=4
XM2 Y n1 VSS VSUBS nfet_03v3 w=0.72u l=0.28u m=12
XM3 n1 A VDD VNW pfet_03v3 w=1.38u l=0.28u m=4
XM4 Y n1 VDD VNW pfet_03v3 w=1.38u l=0.28u m=12
.ends

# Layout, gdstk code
import gdstk
lib = gdstk.Library(unit=1e-6, precision=1e-09)
def R(c, l, rs):  # rectangles x0, y0, x1, y1
    for r in rs: c.add(gdstk.rectangle(r[:2], r[2:], *l))
def A(c, l, x, y, w, h, nx, ny, dx, dy):  # array of equal rectangles
    R(c, l, [(x+i*dx, y+j*dy, x+i*dx+w, y+j*dy+h) for i in range(nx) for j in range(ny)])
boundary = (0, 0)
nwell = (21, 0)
nwell_10 = (21, 10)
comp = (22, 0)
poly2 = (30, 0)
pplus = (31, 0)
nplus = (32, 0)
contact = (33, 0)
metal1 = (34, 0)
metal1_pin = (34, 10)
lvpwell = (204, 0)
lvpwell_10 = (204, 10)

gf180mcu_as_sc_mcu7t3v3_ = lib.new_cell('gf180mcu_as_sc_mcu7t3v3__clkbuff_12')
R(gf180mcu_as_sc_mcu7t3v3_, boundary, [(0,0,14,3.92)])
R(gf180mcu_as_sc_mcu7t3v3_, nwell, [(-0.43,1.77,14.43,4.35)])
R(gf180mcu_as_sc_mcu7t3v3_, nwell_10, [(0.05,3.67,0.55,4.17)])
R(gf180mcu_as_sc_mcu7t3v3_, comp, [(0.14,0.34,13.86,1.06), (0.14,2.2,13.86,3.58)])
A(gf180mcu_as_sc_mcu7t3v3_, poly2, 0.58, 0.12, 0.28, 1.45, 9, 1, 0.8, 0)
A(gf180mcu_as_sc_mcu7t3v3_, poly2, 9.395, 0.12, 0.28, 1.54, 5, 1, 0.8, 0)
A(gf180mcu_as_sc_mcu7t3v3_, poly2, 9.395, 1.905, 0.28, 1.895, 5, 1, 0.8, 0)
A(gf180mcu_as_sc_mcu7t3v3_, poly2, 0.58, 2.015, 0.28, 1.785, 9, 1, 0.8, 0)
R(gf180mcu_as_sc_mcu7t3v3_, poly2, [(7.78,0.12,8.06,1.66), (8.58,0.12,8.86,1.66), (0.515,1.57,3.26,2.015), (3.78,1.57,7.26,1.66), (3.78,1.66,12.875,1.905), (3.78,1.905,7.26,2.015), (7.78,1.905,8.06,3.8), (8.58,1.905,8.86,3.8)])
R(gf180mcu_as_sc_mcu7t3v3_, pplus, [(-0.2,1.77,14.2,4.12)])
R(gf180mcu_as_sc_mcu7t3v3_, nplus, [(-0.2,-0.2,14.2,1.77)])
A(gf180mcu_as_sc_mcu7t3v3_, contact, 5.01, 0.41, 0.22, 0.22, 3, 1, 1.6, 0)
A(gf180mcu_as_sc_mcu7t3v3_, contact, 9.825, 0.41, 0.22, 0.22, 3, 2, 1.6, 1.925)
A(gf180mcu_as_sc_mcu7t3v3_, contact, 1.01, 0.59, 0.22, 0.22, 5, 1, 1.6, 0)
A(gf180mcu_as_sc_mcu7t3v3_, contact, 9.025, 0.59, 0.22, 0.22, 3, 2, 1.6, 1.865)
A(gf180mcu_as_sc_mcu7t3v3_, contact, 3.96, 1.665, 0.22, 0.22, 7, 1, 0.47, 0)
A(gf180mcu_as_sc_mcu7t3v3_, contact, 0.81, 1.685, 0.22, 0.22, 5, 1, 0.47, 0)
A(gf180mcu_as_sc_mcu7t3v3_, contact, 8.21, 2.335, 0.22, 0.22, 1, 3, 0, 0.47)
A(gf180mcu_as_sc_mcu7t3v3_, contact, 4.21, 2.5, 0.22, 0.22, 3, 2, 1.6, 0.47)
A(gf180mcu_as_sc_mcu7t3v3_, contact, 9.825, 2.805, 0.22, 0.22, 3, 2, 1.6, 0.47)
A(gf180mcu_as_sc_mcu7t3v3_, contact, 9.025, 2.925, 0.22, 0.22, 3, 1, 1.6, 0)
R(gf180mcu_as_sc_mcu7t3v3_, contact, [(1.81,0.41,2.03,0.63), (0.21,0.415,0.43,0.635), (3.41,0.415,3.63,0.635), (2.61,2.475,2.83,2.695), (1.01,2.5,1.23,2.72), (2.61,2.945,2.83,3.165), (1.01,2.97,1.23,3.19), (1.81,3.05,2.03,3.27), (6.61,3.055,6.83,3.275), (3.41,3.06,3.63,3.28), (5.01,3.06,5.23,3.28), (0.21,3.12,0.43,3.34)])
A(gf180mcu_as_sc_mcu7t3v3_, metal1, 1.805, 0.3, 0.23, 0.41, 4, 1, 1.6, 0)
A(gf180mcu_as_sc_mcu7t3v3_, metal1, 9.82, 0.3, 0.23, 0.39, 3, 1, 1.6, 0)
A(gf180mcu_as_sc_mcu7t3v3_, metal1, 1.005, 0.53, 0.23, 0.57, 5, 1, 1.6, 0)
A(gf180mcu_as_sc_mcu7t3v3_, metal1, 9.02, 0.53, 0.23, 1, 3, 1, 1.6, 0)
A(gf180mcu_as_sc_mcu7t3v3_, metal1, 9.02, 2.035, 0.23, 1.355, 3, 1, 1.6, 0)
A(gf180mcu_as_sc_mcu7t3v3_, metal1, 9.82, 2.265, 0.23, 1.355, 3, 1, 1.6, 0)
A(gf180mcu_as_sc_mcu7t3v3_, metal1, 1.005, 2.535, 0.23, 0.855, 5, 1, 1.6, 0)
R(gf180mcu_as_sc_mcu7t3v3_, metal1, [(0,-0.3,14,0.3), (0.205,0.3,0.435,0.7), (8.205,0.3,8.435,0.69), (1.005,1.1,3.605,1.33), (4.205,1.1,7.635,1.33), (3.375,1.33,3.605,1.63), (7.405,1.33,7.635,1.53), (7.405,1.53,12.45,2.035), (0.515,1.57,3.145,2.075), (3.375,1.63,7.175,1.92), (3.375,1.92,3.605,2.305), (7.405,2.035,7.635,2.305), (8.205,2.265,8.435,3.62), (1.005,2.305,3.605,2.535), (4.205,2.305,7.635,2.535), (1.805,2.765,2.035,3.62), (6.605,2.765,6.835,3.62), (3.405,2.77,3.635,3.62), (5.005,2.77,5.235,3.62), (0.205,2.85,0.435,3.62), (0,3.62,14,4.22)])
R(gf180mcu_as_sc_mcu7t3v3_, metal1_pin, [(0,-0.3,14,0.3), (7.405,1.53,12.45,2.035), (0.515,1.57,3.145,2.075), (0,3.62,14,4.22)])
R(gf180mcu_as_sc_mcu7t3v3_, lvpwell, [(-0.43,-0.43,14.43,1.77)])
R(gf180mcu_as_sc_mcu7t3v3_, lvpwell_10, [(0.05,-0.25,0.55,0.25)])
gf180mcu_as_sc_mcu7t3v3_.add(gdstk.Label('VDD', (7,3.92), layer=34, texttype=10))
gf180mcu_as_sc_mcu7t3v3_.add(gdstk.Label('VSS', (7,0), layer=34, texttype=10))
gf180mcu_as_sc_mcu7t3v3_.add(gdstk.Label('A', (1.83,1.822), layer=34, texttype=10))
gf180mcu_as_sc_mcu7t3v3_.add(gdstk.Label('Y', (9.927,1.782), layer=34, texttype=10))
gf180mcu_as_sc_mcu7t3v3_.add(gdstk.Label('VNW', (0.3,3.92), layer=21, texttype=10))
gf180mcu_as_sc_mcu7t3v3_.add(gdstk.Label('VPW', (0.3,0), layer=204, texttype=10))

lib.write_gds('gf180mcu_as_sc_mcu7t3v3__clkbuff_12.gds')
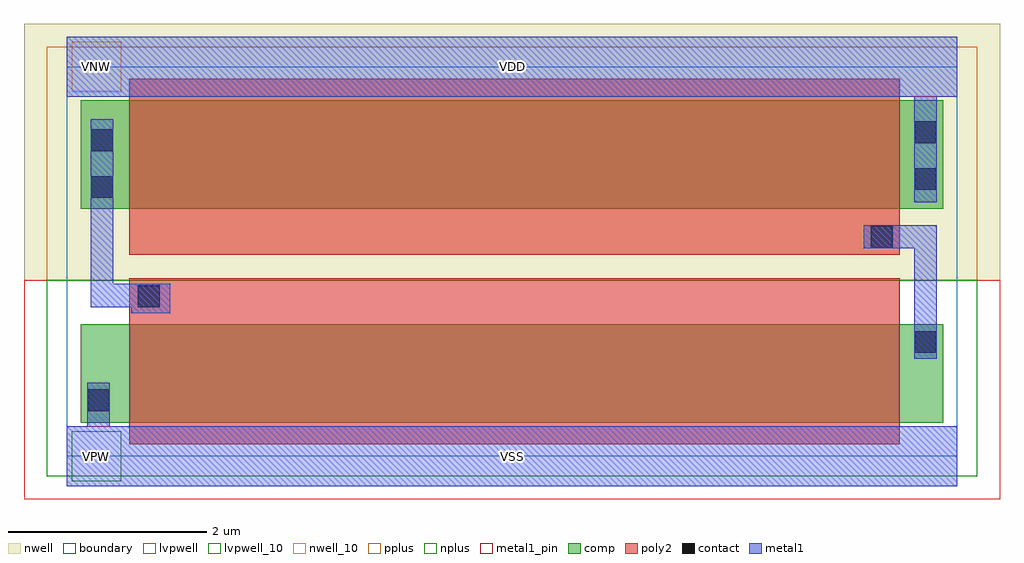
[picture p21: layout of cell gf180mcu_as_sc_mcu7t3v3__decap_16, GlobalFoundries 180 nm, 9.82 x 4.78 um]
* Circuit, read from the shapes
.subckt gf180mcu_as_sc_mcu7t3v3__decap_16 VDD VNW VSS
XM1 n1 n2 VSS VSUBS nfet_03v3 w=0.99u l=7.75u
XM2 VDD n1 n2 VNW pfet_03v3 w=1.09u l=7.75u
.ends

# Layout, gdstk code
import gdstk
lib = gdstk.Library(unit=1e-6, precision=1e-09)
def R(c, l, rs):  # rectangles x0, y0, x1, y1
    for r in rs: c.add(gdstk.rectangle(r[:2], r[2:], *l))
boundary = (0, 0)
nwell = (21, 0)
nwell_10 = (21, 10)
comp = (22, 0)
poly2 = (30, 0)
pplus = (31, 0)
nplus = (32, 0)
contact = (33, 0)
metal1 = (34, 0)
metal1_pin = (34, 10)
lvpwell = (204, 0)
lvpwell_10 = (204, 10)

gf180mcu_as_sc_mcu7t3v3_ = lib.new_cell('gf180mcu_as_sc_mcu7t3v3__decap_16')
R(gf180mcu_as_sc_mcu7t3v3_, boundary, [(0,0,8.96,3.92)])
R(gf180mcu_as_sc_mcu7t3v3_, nwell, [(-0.43,1.77,9.39,4.35)])
R(gf180mcu_as_sc_mcu7t3v3_, nwell_10, [(0.05,3.67,0.55,4.17)])
R(gf180mcu_as_sc_mcu7t3v3_, comp, [(0.14,0.34,8.82,1.33), (0.14,2.49,8.82,3.58)])
R(gf180mcu_as_sc_mcu7t3v3_, poly2, [(0.63,0.12,8.38,1.79), (0.63,2.03,8.38,3.8)])
R(gf180mcu_as_sc_mcu7t3v3_, pplus, [(-0.2,1.77,9.16,4.12)])
R(gf180mcu_as_sc_mcu7t3v3_, nplus, [(-0.2,-0.2,9.16,1.77)])
R(gf180mcu_as_sc_mcu7t3v3_, contact, [(0.21,0.455,0.43,0.675), (8.53,1.04,8.75,1.26), (0.715,1.5,0.935,1.72), (8.09,2.1,8.31,2.32), (0.245,2.6,0.465,2.82), (8.53,2.68,8.75,2.9), (0.245,3.07,0.465,3.29), (8.53,3.15,8.75,3.37)])
R(gf180mcu_as_sc_mcu7t3v3_, metal1, [(0,-0.3,8.96,0.3), (0.205,0.3,0.435,0.74), (8.525,0.98,8.755,2.095), (0.65,1.44,1.04,1.5), (0.24,1.5,1.04,1.735), (0.24,1.735,0.47,3.39), (8.02,2.095,8.755,2.325), (8.525,2.555,8.755,3.62), (0,3.62,8.96,4.22)])
R(gf180mcu_as_sc_mcu7t3v3_, metal1_pin, [(0,-0.3,8.96,0.3), (0,3.62,8.96,4.22)])
R(gf180mcu_as_sc_mcu7t3v3_, lvpwell, [(-0.43,-0.43,9.39,1.77)])
R(gf180mcu_as_sc_mcu7t3v3_, lvpwell_10, [(0.05,-0.25,0.55,0.25)])
gf180mcu_as_sc_mcu7t3v3_.add(gdstk.Label('VDD', (4.48,3.92), layer=34, texttype=10))
gf180mcu_as_sc_mcu7t3v3_.add(gdstk.Label('VSS', (4.48,0), layer=34, texttype=10))
gf180mcu_as_sc_mcu7t3v3_.add(gdstk.Label('VNW', (0.3,3.92), layer=21, texttype=10))
gf180mcu_as_sc_mcu7t3v3_.add(gdstk.Label('VPW', (0.3,0), layer=204, texttype=10))

lib.write_gds('gf180mcu_as_sc_mcu7t3v3__decap_16.gds')
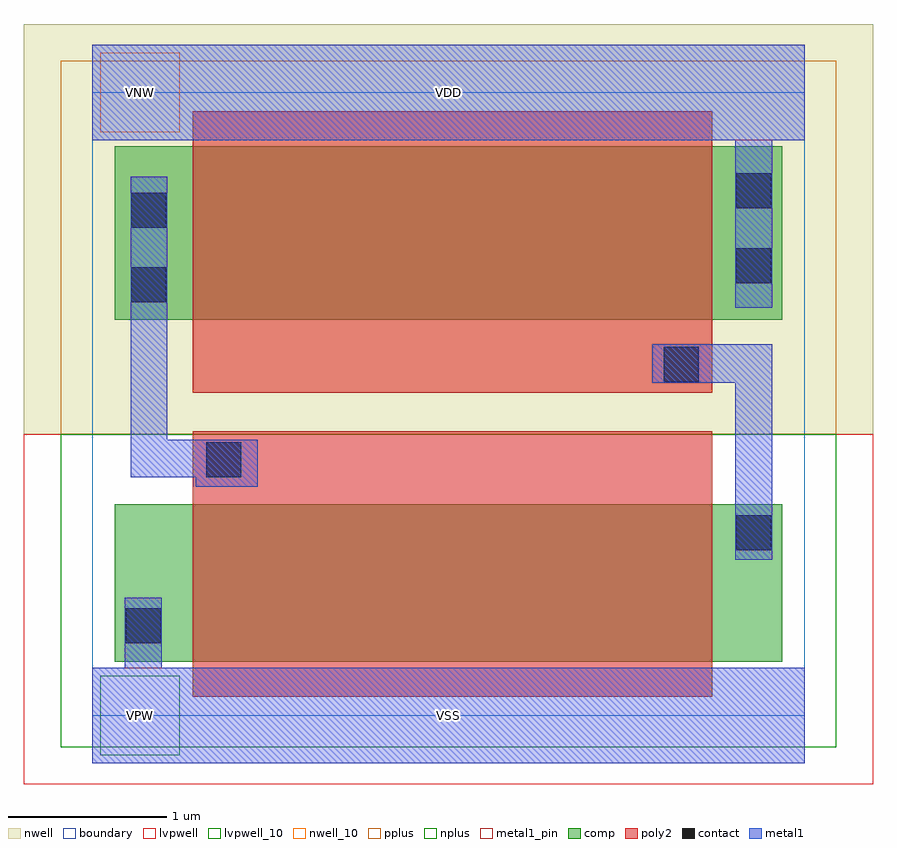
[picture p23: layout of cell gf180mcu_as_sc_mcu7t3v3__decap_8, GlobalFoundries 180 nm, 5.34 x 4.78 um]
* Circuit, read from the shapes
.subckt gf180mcu_as_sc_mcu7t3v3__decap_8 VDD VNW VSS
XM1 n1 n2 VSS VSUBS nfet_03v3 w=0.99u l=3.27u
XM2 VDD n1 n2 VNW pfet_03v3 w=1.09u l=3.27u
.ends

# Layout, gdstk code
import gdstk
lib = gdstk.Library(unit=1e-6, precision=1e-09)
def R(c, l, rs):  # rectangles x0, y0, x1, y1
    for r in rs: c.add(gdstk.rectangle(r[:2], r[2:], *l))
boundary = (0, 0)
nwell = (21, 0)
nwell_10 = (21, 10)
comp = (22, 0)
poly2 = (30, 0)
pplus = (31, 0)
nplus = (32, 0)
contact = (33, 0)
metal1 = (34, 0)
metal1_pin = (34, 10)
lvpwell = (204, 0)
lvpwell_10 = (204, 10)

gf180mcu_as_sc_mcu7t3v3_ = lib.new_cell('gf180mcu_as_sc_mcu7t3v3__decap_8')
R(gf180mcu_as_sc_mcu7t3v3_, boundary, [(0,0,4.48,3.92)])
R(gf180mcu_as_sc_mcu7t3v3_, nwell, [(-0.43,1.77,4.91,4.35)])
R(gf180mcu_as_sc_mcu7t3v3_, nwell_10, [(0.05,3.67,0.55,4.17)])
R(gf180mcu_as_sc_mcu7t3v3_, comp, [(0.14,0.34,4.34,1.33), (0.14,2.49,4.34,3.58)])
R(gf180mcu_as_sc_mcu7t3v3_, poly2, [(0.63,0.12,3.9,1.79), (0.63,2.03,3.9,3.8)])
R(gf180mcu_as_sc_mcu7t3v3_, pplus, [(-0.2,1.77,4.68,4.12)])
R(gf180mcu_as_sc_mcu7t3v3_, nplus, [(-0.2,-0.2,4.68,1.77)])
R(gf180mcu_as_sc_mcu7t3v3_, contact, [(0.21,0.455,0.43,0.675), (4.05,1.04,4.27,1.26), (0.715,1.5,0.935,1.72), (3.595,2.1,3.815,2.32), (0.245,2.6,0.465,2.82), (4.05,2.72,4.27,2.94), (0.245,3.07,0.465,3.29), (4.05,3.19,4.27,3.41)])
R(gf180mcu_as_sc_mcu7t3v3_, metal1, [(0,-0.3,4.48,0.3), (0.205,0.3,0.435,0.74), (4.045,0.98,4.275,2.095), (0.65,1.44,1.04,1.5), (0.24,1.5,1.04,1.735), (0.24,1.735,0.47,3.39), (3.52,2.095,4.275,2.335), (4.045,2.565,4.275,3.62), (0,3.62,4.48,4.22)])
R(gf180mcu_as_sc_mcu7t3v3_, metal1_pin, [(0,-0.3,4.48,0.3), (0,3.62,4.48,4.22)])
R(gf180mcu_as_sc_mcu7t3v3_, lvpwell, [(-0.43,-0.43,4.91,1.77)])
R(gf180mcu_as_sc_mcu7t3v3_, lvpwell_10, [(0.05,-0.25,0.55,0.25)])
gf180mcu_as_sc_mcu7t3v3_.add(gdstk.Label('VDD', (2.24,3.92), layer=34, texttype=10))
gf180mcu_as_sc_mcu7t3v3_.add(gdstk.Label('VSS', (2.24,0), layer=34, texttype=10))
gf180mcu_as_sc_mcu7t3v3_.add(gdstk.Label('VNW', (0.3,3.92), layer=21, texttype=10))
gf180mcu_as_sc_mcu7t3v3_.add(gdstk.Label('VPW', (0.3,0), layer=204, texttype=10))

lib.write_gds('gf180mcu_as_sc_mcu7t3v3__decap_8.gds')
